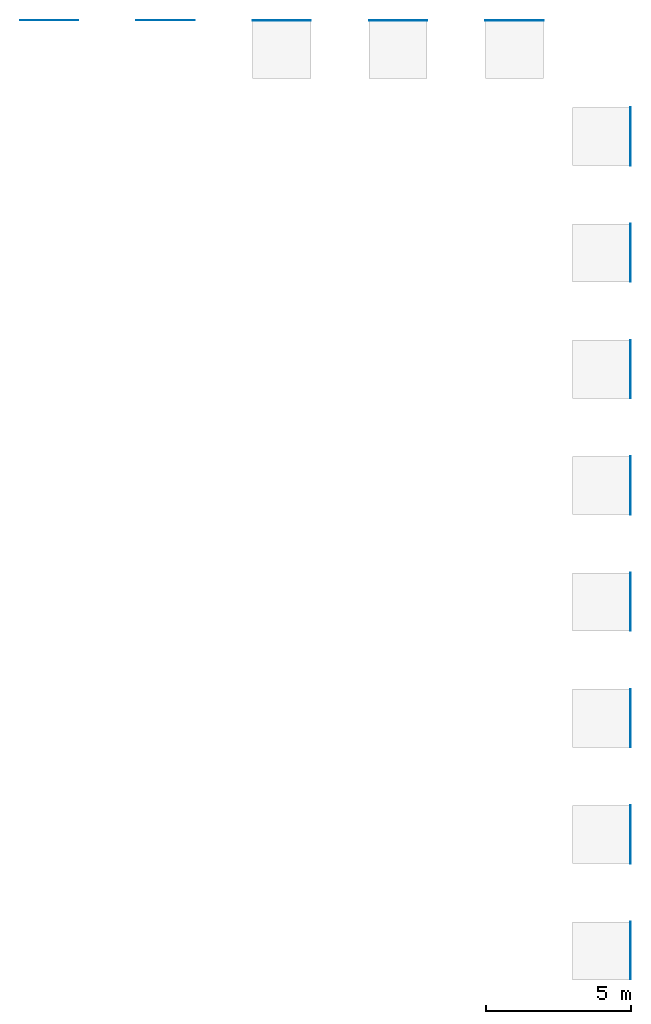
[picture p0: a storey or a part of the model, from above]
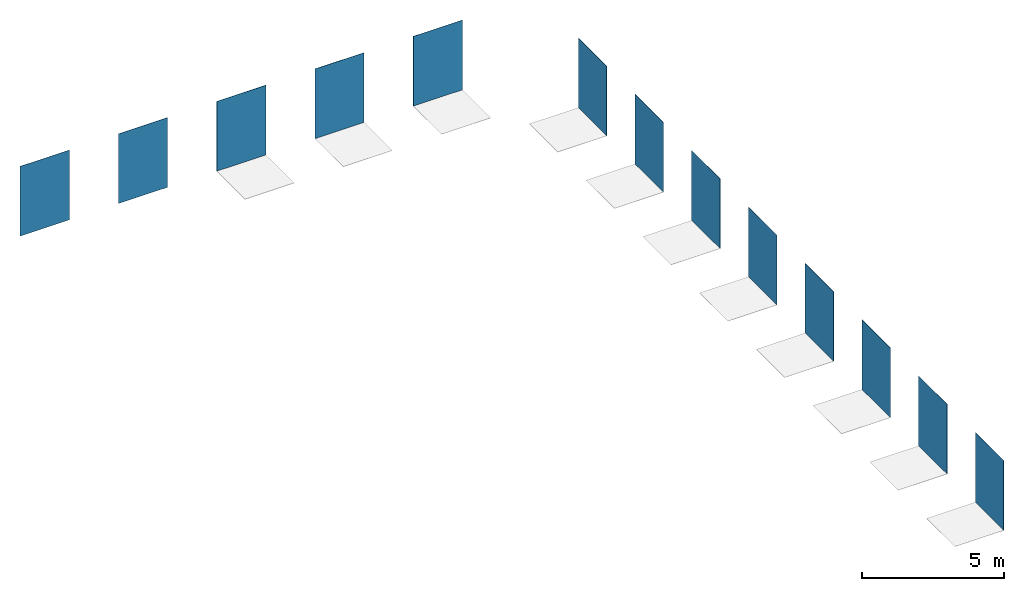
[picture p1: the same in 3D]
Properties of the parts of a building model (IFC2X3), part 2 of 2

# IfcWallStandardCase: Basic Wall:PGR_Porcelanosa_CeramicTiles_Boston_Grafito_Antislip-435x659mm-100180940, Basic Wall:PGR_Porcelanosa_CeramicTiles_Boston_Grafito_Antislip-435x659mm-100180940:212718
Type - NBS_Data - HasSurfaceRoughness: no; AbrasionResistance: 6: Intense-External Access; BreakingStrength: Average Value: 3310 N (Min. 1300 N); ChemicalResistance: Class 'A' for swimming pools and cleaning products (resists attack); minimum Class 'B' for acids and bases; Collection: STON-KER; CreationDate: 2018/07; Dcof: >0.42; FlexuralStrength: >40 N/mm²; FrostResistance: Conforms to ISO 10545-9; Group: BIa; MoistureExpansion: <0.1 mm/m; RampTest: R-12; RecycledContent: >6.5%; Series: Boston; SlipResistanceValuePendulumTestValue: CL3; StainResistance: Class 5: Easy cleaning with water; SurfaceQuality: Without surface defects; ThermalShockResistance: Conforms to ISO 10545–12; UpecC: n/a; UpecE: n/a; UpecP: n/a; UpecU: n/a; WaterAbsorption: E<=0.5%
COBie - AssetIdentifier: n/a; BarCode: n/a; InstallationDate: 1900-12-31T23:59:59; TagNumber: n/a; WarrantyStartDate: 1900-12-31T23:59:59

# IfcWallStandardCase: Basic Wall:PGR_Porcelanosa_CeramicTiles_Boston_Stone-435x659mm-100179183, Basic Wall:PGR_Porcelanosa_CeramicTiles_Boston_Stone-435x659mm-100179183:212739
In: Level 1
Type - PredefinedType: STANDARD; Material: PGR_Porcelanosa_CeramicTiles_Boston_Stone-435x659mm-100179183 10.5 mm
Type - NBS_General - Author: Porcelanosa Group; BIMObjectName: PGR_Porcelanosa_CeramicTiles_Boston_Stone-435x659mm-100179183; ManufacturerURL: www.porcelanosa.com; NBSDescription: Ceramic Tiles; NBSReference: 45-80-95/310; ProductInformation: http://calidad.info-grupo.com:8081/GeneraFicha3/PDF?articulo=100179183&lang=EN&un=0; Revision: n/a; Uniclass2015Code: Pr_35_93_96_19; Uniclass2015Title: Ceramic Tiles; Uniclass2015Version: Products v1.5; Version: 1
Type - COBie - AccessibilityPerformance: See ProductInformation (Technical PDF); AssetType: Fixed; Category: Walls; CodePerformance: ISO-13006:2012; UNE-EN 14411:2012; Color: Gris; Constituents: Clays, feldespat and glaze; Description: Rectified Porcelain tiles, BOSTON series from PORCELANOSA, GRIS color and MATTE finish, 43.5x65.9 cm (10.5 mm thickness), group BIa, according to UNE-EN 14411, water absortion capacity E<=0.5%, flexural strength >40 N/mm², breaking strength with an average value of 3310 N (Min. 1300 N) and slip resistance R-9; DurationUnit: year; ExpectedLife: 50; Features: See ProductInformation (Technical PDF); Grade: First quality; Manufacturer: bim.gp@porcelanosagrupo.com; ModelNumber: 100179183; ModelReference: Boston Stone 43.5x65.9 cm; Name: CeramicTiles_Boston_Stone-435x659mm-100179183; NominalHeight: 10.5 mm; NominalLength: 659 mm; NominalWidth: 435 mm; ReplacementCost: n/a; Shape: Rectangular; Size: 435x659x10.5 mm; Sustainability Performance: See ProductInformation (Technical PDF); WarrantyDescription: Manufacturer warranty, applicable worldwide, with the pertinent national legislation prevailing in all cases and covering at least a 3-year period; all products must have been manufactured and fitted in accordance with the Fabricator's Manual, and have been used and cared for in accordance with the Guide to Use, Cleaning and Care available on the web page www.porcelanosa.com; WarrantyDurationLabor: n/a; WarrantyDurationParts: 3; WarrantyDurationUnit: year; WarrantyGuarantorLabor: n/a; WarrantyGuarantorParts: bim.gp@porcelanosagrupo.com
Type - Pset_CoveringCommon - IsExternal: yes; Reference: n/a; AcousticRating: n/a; Finish: Tone Variations, Matte, Rectified, Stone; FireRating: A1; FlammabilityRating: Class 0; FragilityRating: n/a; Material: Ceramic; SurfaceSpreadOfFlame: Class 0; ThermalTransmittance: 219.048 kg/K/s3; TotalThickness: 10.5 mm
Type - IFC - IfcExportType: FLOORING; IfcExportAS: IfcCovering
Type - NBS_Data - HasSurfaceRoughness: no; AbrasionResistance: 6: Intense-External Access; BreakingStrength: Average Value: 3310 N (Min. 1300 N); ChemicalResistance: Class 'A' for swimming pools and cleaning products (resists attack); minimum Class 'B' for acids and bases; Collection: STON-KER; CreationDate: 2018/07; Dcof: >0.42; FlexuralStrength: >40 N/mm²; FrostResistance: Conforms to ISO 10545-9; Group: BIa; MoistureExpansion: <0.1 mm/m; RampTest: R-9; RecycledContent: >6.5%; Series: Boston; SlipResistanceValuePendulumTestValue: n/a; StainResistance: Class 5: Easy cleaning with water; SurfaceQuality: Without surface defects; ThermalShockResistance: Conforms to ISO 10545–12; UpecC: 2; UpecE: 3; UpecP: 3; UpecU: 2S; WaterAbsorption: E<=0.5%
COBie - AssetIdentifier: n/a; BarCode: n/a; InstallationDate: 1900-12-31T23:59:59; TagNumber: n/a; WarrantyStartDate: 1900-12-31T23:59:59

# IfcWallStandardCase: Basic Wall:PGR_Porcelanosa_CeramicTiles_Boston_Stone-596x1800mm-100179318, Basic Wall:PGR_Porcelanosa_CeramicTiles_Boston_Stone-596x1800mm-100179318:213871
In: Level 1
Type - PredefinedType: STANDARD; Material: PGR_Porcelanosa_CeramicTiles_Boston_Stone-596x1800mm-100179318 11.5 mm
Type - NBS_General - Author: Porcelanosa Group; BIMObjectName: PGR_Porcelanosa_CeramicTiles_Boston_Stone-596x1800mm-100179318; ManufacturerURL: www.porcelanosa.com; NBSDescription: Ceramic Tiles; NBSReference: 45-80-95/310; ProductInformation: http://calidad.info-grupo.com:8081/GeneraFicha3/PDF?articulo=100179318&lang=EN&un=0; Revision: n/a; Uniclass2015Code: Pr_35_93_96_19; Uniclass2015Title: Ceramic Tiles; Uniclass2015Version: Products v1.5; Version: 1
Type - COBie - AccessibilityPerformance: See ProductInformation (Technical PDF); AssetType: Fixed; Category: Walls; CodePerformance: ISO-13006:2012; UNE-EN 14411:2012; Color: Gris; Constituents: Clays, feldespat and glaze; Description: Rectified Porcelain tiles, BOSTON series from PORCELANOSA, GRIS color and MATTE finish, 59.6x180 cm (11.5 mm thickness), group BIa, according to UNE-EN 14411, water absortion capacity E<=0.5%, flexural strength >40 N/mm², breaking strength with an average value of 3310 N (Min. 1300 N) and slip resistance R-9; DurationUnit: year; ExpectedLife: 50; Features: See ProductInformation (Technical PDF); Grade: First quality; Manufacturer: bim.gp@porcelanosagrupo.com; ModelNumber: 100179318; ModelReference: Boston Stone 59.6x180 cm; Name: CeramicTiles_Boston_Stone-596x1800mm-100179318; NominalHeight: 11.5 mm; NominalLength: 1800 mm; NominalWidth: 596 mm; ReplacementCost: n/a; Shape: Rectangular; Size: 596x1800x11.5 mm; Sustainability Performance: See ProductInformation (Technical PDF); WarrantyDescription: Manufacturer warranty, applicable worldwide, with the pertinent national legislation prevailing in all cases and covering at least a 3-year period; all products must have been manufactured and fitted in accordance with the Fabricator's Manual, and have been used and cared for in accordance with the Guide to Use, Cleaning and Care available on the web page www.porcelanosa.com; WarrantyDurationLabor: n/a; WarrantyDurationParts: 3; WarrantyDurationUnit: year; WarrantyGuarantorLabor: n/a; WarrantyGuarantorParts: bim.gp@porcelanosagrupo.com
Type - Pset_CoveringCommon - IsExternal: yes; Reference: n/a; AcousticRating: n/a; Finish: Tone Variations, Matte, Rectified, Stone; FireRating: A1; FlammabilityRating: Class 0; FragilityRating: n/a; Material: Ceramic; SurfaceSpreadOfFlame: Class 0; ThermalTransmittance: 200 kg/K/s3; TotalThickness: 11.5 mm
Type - IFC - IfcExportType: FLOORING; IfcExportAS: IfcCovering
Type - NBS_Data - HasSurfaceRoughness: no; AbrasionResistance: 6: Intense-External Access; BreakingStrength: Average Value: 3310 N (Min. 1300 N); ChemicalResistance: Class 'A' for swimming pools and cleaning products (resists attack); minimum Class 'B' for acids and bases; Collection: STON-KER; CreationDate: 2018/07; Dcof: >0.42; FlexuralStrength: >40 N/mm²; FrostResistance: Conforms to ISO 10545-9; Group: BIa; MoistureExpansion: <0.1 mm/m; RampTest: R-9; RecycledContent: >6.5%; Series: Boston; SlipResistanceValuePendulumTestValue: CL1; StainResistance: Class 5: Easy cleaning with water; SurfaceQuality: Without surface defects; ThermalShockResistance: Conforms to ISO 10545–12; UpecC: n/a; UpecE: n/a; UpecP: n/a; UpecU: n/a; WaterAbsorption: E<=0.5%
COBie - AssetIdentifier: n/a; BarCode: n/a; InstallationDate: 1900-12-31T23:59:59; TagNumber: n/a; WarrantyStartDate: 1900-12-31T23:59:59

# IfcWallStandardCase: Basic Wall:PGR_Porcelanosa_CeramicTiles_Boston_Stone_Antislip-435x659mm-100180941, Basic Wall:PGR_Porcelanosa_CeramicTiles_Boston_Stone_Antislip-435x659mm-100180941:212760
In: Level 1
Type - PredefinedType: STANDARD; Material: PGR_Porcelanosa_CeramicTiles_Boston_Stone_Antislip-435x659mm-100180941 10.5 mm
Type - NBS_General - Author: Porcelanosa Group; BIMObjectName: PGR_Porcelanosa_CeramicTiles_Boston_Stone_Ant.-435x659mm-100180941; ManufacturerURL: www.porcelanosa.com; NBSDescription: Ceramic Tiles; NBSReference: 45-80-95/310; ProductInformation: http://calidad.info-grupo.com:8081/GeneraFicha3/PDF?articulo=100180941&lang=EN&un=0; Revision: n/a; Uniclass2015Code: Pr_35_93_96_19; Uniclass2015Title: Ceramic Tiles; Uniclass2015Version: Products v1.5; Version: 1
Type - COBie - AccessibilityPerformance: See ProductInformation (Technical PDF); AssetType: Fixed; Category: Walls; CodePerformance: ISO-13006:2012; UNE-EN 14411:2012; Color: Gris; Constituents: Clays, feldespat and glaze; Description: Rectified Porcelain tiles, BOSTON series from PORCELANOSA, GRIS color and MATTE finish, 43.5x65.9 cm (10.5 mm thickness), group BIa, according to UNE-EN 14411, water absortion capacity E<=0.5%, flexural strength >40 N/mm², breaking strength with an average value of 3310 N (Min. 1300 N) and slip resistance R-12; DurationUnit: year; ExpectedLife: 50; Features: See ProductInformation (Technical PDF); Grade: First quality; Manufacturer: bim.gp@porcelanosagrupo.com; ModelNumber: 100180941; ModelReference: Boston Stone Ant. 43.5x65.9 cm; Name: CeramicTiles_Boston_Stone_Ant.-435x659mm-100180941; NominalHeight: 10.5 mm; NominalLength: 659 mm; NominalWidth: 435 mm; ReplacementCost: n/a; Shape: Rectangular; Size: 435x659x10.5 mm; Sustainability Performance: See ProductInformation (Technical PDF); WarrantyDescription: Manufacturer warranty, applicable worldwide, with the pertinent national legislation prevailing in all cases and covering at least a 3-year period; all products must have been manufactured and fitted in accordance with the Fabricator's Manual, and have been used and cared for in accordance with the Guide to Use, Cleaning and Care available on the web page www.porcelanosa.com; WarrantyDurationLabor: n/a; WarrantyDurationParts: 3; WarrantyDurationUnit: year; WarrantyGuarantorLabor: n/a; WarrantyGuarantorParts: bim.gp@porcelanosagrupo.com
Type - Pset_CoveringCommon - IsExternal: yes; Reference: n/a; AcousticRating: n/a; Finish: Tone Variations, Matte, Non-Slip, Rectified, Stone; FireRating: A1; FlammabilityRating: Class 0; FragilityRating: n/a; Material: Ceramic; SurfaceSpreadOfFlame: Class 0; ThermalTransmittance: 219.048 kg/K/s3; TotalThickness: 10.5 mm
Type - IFC - IfcExportType: FLOORING; IfcExportAS: IfcCovering
Type - NBS_Data - HasSurfaceRoughness: no; AbrasionResistance: 6: Intense-External Access; BreakingStrength: Average Value: 3310 N (Min. 1300 N); ChemicalResistance: Class 'A' for swimming pools and cleaning products (resists attack); minimum Class 'B' for acids and bases; Collection: STON-KER; CreationDate: 2018/07; Dcof: >0.42; FlexuralStrength: >40 N/mm²; FrostResistance: Conforms to ISO 10545-9; Group: BIa; MoistureExpansion: <0.1 mm/m; RampTest: R-12; RecycledContent: >6.5%; Series: Boston; SlipResistanceValuePendulumTestValue: CL3; StainResistance: Class 5: Easy cleaning with water; SurfaceQuality: Without surface defects; ThermalShockResistance: Conforms to ISO 10545–12; UpecC: n/a; UpecE: n/a; UpecP: n/a; UpecU: n/a; WaterAbsorption: E<=0.5%
COBie - AssetIdentifier: n/a; BarCode: n/a; InstallationDate: 1900-12-31T23:59:59; TagNumber: n/a; WarrantyStartDate: 1900-12-31T23:59:59

# IfcWallStandardCase: Basic Wall:PGR_Porcelanosa_CeramicTiles_Boston_Topo-316x900mm-100179290, Basic Wall:PGR_Porcelanosa_CeramicTiles_Boston_Topo-316x900mm-100179290:219437
In: Level 1
Type - PredefinedType: STANDARD; Material: PGR_Porcelanosa_CeramicTiles_Boston_Topo-316x900mm-100179290 9 mm
Type - NBS_General - Author: Porcelanosa Group; BIMObjectName: PGR_Porcelanosa_CeramicTiles_Boston_Topo-316x900mm-100179290; ManufacturerURL: www.porcelanosa.com; NBSDescription: Ceramic Tiles; NBSReference: 45-80-95/310; ProductInformation: http://calidad.info-grupo.com:8081/GeneraFicha3/PDF?articulo=100179290&lang=EN&un=0; Revision: n/a; Uniclass2015Code: Pr_35_93_96_19; Uniclass2015Title: Ceramic Tiles; Uniclass2015Version: Products v1.5; Version: 1
Type - COBie - AccessibilityPerformance: See ProductInformation (Technical PDF); AssetType: Fixed; Category: Walls; CodePerformance: ISO-13006:2012; UNE-EN 14411:2012; Color: Marron; Constituents: Clays, feldespat and glaze; Description: Rectified Monoporous, BOSTON series from PORCELANOSA, MARRON color and MATTE finish, 31.6x90 cm (9 mm thickness), group BIII, according to UNE-EN 14411, water absortion capacity 10%<=E<=20%, flexural strength >23 N/mm² and breaking strength with an average value of 1337 N (Min. 600 N); DurationUnit: year; ExpectedLife: 50; Features: See ProductInformation (Technical PDF); Grade: First quality; Manufacturer: bim.gp@porcelanosagrupo.com; ModelNumber: 100179290; ModelReference: Boston Topo 31.6x90 cm; Name: CeramicTiles_Boston_Topo-316x900mm-100179290; NominalHeight: 9 mm; NominalLength: 900 mm; NominalWidth: 316 mm; ReplacementCost: n/a; Shape: Rectangular; Size: 316x900x9 mm; Sustainability Performance: See ProductInformation (Technical PDF); WarrantyDescription: Manufacturer warranty, applicable worldwide, with the pertinent national legislation prevailing in all cases and covering at least a 3-year period; all products must have been manufactured and fitted in accordance with the Fabricator's Manual, and have been used and cared for in accordance with the Guide to Use, Cleaning and Care available on the web page www.porcelanosa.com; WarrantyDurationLabor: n/a; WarrantyDurationParts: 3; WarrantyDurationUnit: year; WarrantyGuarantorLabor: n/a; WarrantyGuarantorParts: bim.gp@porcelanosagrupo.com
Type - Pset_CoveringCommon - Reference: n/a; AcousticRating: n/a; Finish: Tone Variations, Matte, Rectified, Stone; FireRating: A1; FlammabilityRating: Class 0; FragilityRating: n/a; IsExternal: no; Material: Ceramic; SurfaceSpreadOfFlame: Class 0; ThermalTransmittance: 255.556 kg/K/s3; TotalThickness: 9 mm
Type - IFC - IfcExportType: CLADDING; IfcExportAS: IfcCovering
Type - NBS_Data - HasSurfaceRoughness: no; AbrasionResistance: 1: Wall Tiles; BreakingStrength: Average Value: 1337 N (Min. 600 N); ChemicalResistance: Class 'A' for swimming pools and cleaning products (resists attack); minimum Class 'B' for acids and bases; Collection: Revestimiento Ceramico Rectificado; CreationDate: 2018/07; Dcof: n/a; FlexuralStrength: >23 N/mm²; FrostResistance: n/a; Group: BIII; MoistureExpansion: <0.1 mm/m; RampTest: n/a; RecycledContent: >18%; Series: Boston; SlipResistanceValuePendulumTestValue: n/a; StainResistance: Class 5: Easy cleaning with water; SurfaceQuality: Without surface defects; ThermalShockResistance: Conforms to ISO 10545–12; UpecC: n/a; UpecE: n/a; UpecP: n/a; UpecU: n/a; WaterAbsorption: 10%<=E<=20%
COBie - AssetIdentifier: n/a; BarCode: n/a; InstallationDate: 1900-12-31T23:59:59; TagNumber: n/a; WarrantyStartDate: 1900-12-31T23:59:59

# IfcWallStandardCase: Basic Wall:PGR_Porcelanosa_CeramicTiles_Boston_Topo-435x659mm-100179203, Basic Wall:PGR_Porcelanosa_CeramicTiles_Boston_Topo-435x659mm-100179203:212781
In: Level 1
Type - PredefinedType: STANDARD; Material: PGR_Porcelanosa_CeramicTiles_Boston_Topo-435x659mm-100179203 10.5 mm
Type - NBS_General - Author: Porcelanosa Group; BIMObjectName: PGR_Porcelanosa_CeramicTiles_Boston_Topo-435x659mm-100179203; ManufacturerURL: www.porcelanosa.com; NBSDescription: Ceramic Tiles; NBSReference: 45-80-95/310; ProductInformation: http://calidad.info-grupo.com:8081/GeneraFicha3/PDF?articulo=100179203&lang=EN&un=0; Revision: n/a; Uniclass2015Code: Pr_35_93_96_19; Uniclass2015Title: Ceramic Tiles; Uniclass2015Version: Products v1.5; Version: 1
Type - COBie - AccessibilityPerformance: See ProductInformation (Technical PDF); AssetType: Fixed; Category: Pr_35_93_96_19:Ceramic Tiles; CodePerformance: ISO-13006:2012; UNE-EN 14411:2012; Color: Marron; Constituents: Clays, feldespat and glaze; Description: Rectified Porcelain tiles, BOSTON series from PORCELANOSA, MARRON color and MATTE finish, 43.5x65.9 cm (10.5 mm thickness), group BIa, according to UNE-EN 14411, water absortion capacity E<=0.5%, flexural strength >40 N/mm², breaking strength with an average value of 3310 N (Min. 1300 N) and slip resistance R-9; DurationUnit: year; ExpectedLife: 50; Features: See ProductInformation (Technical PDF); Grade: First quality; Manufacturer: bim.gp@porcelanosagrupo.com; ModelNumber: 100179203; ModelReference: Boston Topo 43.5x65.9 cm; Name: CeramicTiles_Boston_Topo-435x659mm-100179203; NominalHeight: 10.5 mm; NominalLength: 659 mm; NominalWidth: 435 mm; ReplacementCost: n/a; Shape: Rectangular; Size: 435x659x10.5 mm; Sustainability Performance: See ProductInformation (Technical PDF); WarrantyDescription: Manufacturer warranty, applicable worldwide, with the pertinent national legislation prevailing in all cases and covering at least a 3-year period; all products must have been manufactured and fitted in accordance with the Fabricator's Manual, and have been used and cared for in accordance with the Guide to Use, Cleaning and Care available on the web page www.porcelanosa.com; WarrantyDurationLabor: n/a; WarrantyDurationParts: 3; WarrantyDurationUnit: year; WarrantyGuarantorLabor: n/a; WarrantyGuarantorParts: bim.gp@porcelanosagrupo.com
Type - Pset_CoveringCommon - IsExternal: yes; Reference: n/a; AcousticRating: n/a; Finish: Tone Variations, Matte, Rectified, Stone; FireRating: A1; FlammabilityRating: Class 0; FragilityRating: n/a; Material: Ceramic; SurfaceSpreadOfFlame: Class 0; ThermalTransmittance: 219.048 kg/K/s3; TotalThickness: 10.5 mm
Type - IFC - IfcExportType: FLOORING; IfcExportAS: IfcCovering
Type - NBS_Data - HasSurfaceRoughness: no; AbrasionResistance: 6: Intense-External Access; BreakingStrength: Average Value: 3310 N (Min. 1300 N); ChemicalResistance: Class 'A' for swimming pools and cleaning products (resists attack); minimum Class 'B' for acids and bases; Collection: STON-KER; CreationDate: 2018/07; Dcof: >0.42; FlexuralStrength: >40 N/mm²; FrostResistance: Conforms to ISO 10545-9; Group: BIa; MoistureExpansion: <0.1 mm/m; RampTest: R-9; RecycledContent: >6.5%; Series: Boston; SlipResistanceValuePendulumTestValue: CL1; StainResistance: Class 5: Easy cleaning with water; SurfaceQuality: Without surface defects; ThermalShockResistance: Conforms to ISO 10545–12; UpecC: 2; UpecE: 3; UpecP: 3; UpecU: 2S; WaterAbsorption: E<=0.5%
COBie - AssetIdentifier: n/a; BarCode: n/a; InstallationDate: 1900-12-31T23:59:59; TagNumber: n/a; WarrantyStartDate: 1900-12-31T23:59:59

# IfcWallStandardCase: Basic Wall:PGR_Porcelanosa_CeramicTiles_Boston_Topo-596x1800mm-100179326, Basic Wall:PGR_Porcelanosa_CeramicTiles_Boston_Topo-596x1800mm-100179326:213892
In: Level 1
Type - PredefinedType: STANDARD; Material: PGR_Porcelanosa_CeramicTiles_Boston_Topo-596x1800mm-100179326 11.5 mm
Type - NBS_General - Author: Porcelanosa Group; BIMObjectName: PGR_Porcelanosa_CeramicTiles_Boston_Topo-596x1800mm-100179326; ManufacturerURL: www.porcelanosa.com; NBSDescription: Ceramic Tiles; NBSReference: 45-80-95/310; ProductInformation: http://calidad.info-grupo.com:8081/GeneraFicha3/PDF?articulo=100179326&lang=EN&un=0; Revision: n/a; Uniclass2015Code: Pr_35_93_96_19; Uniclass2015Title: Ceramic Tiles; Uniclass2015Version: Products v1.5; Version: 1
Type - COBie - AccessibilityPerformance: See ProductInformation (Technical PDF); AssetType: Fixed; Category: Walls; CodePerformance: ISO-13006:2012; UNE-EN 14411:2012; Color: Marron; Constituents: Clays, feldespat and glaze; Description: Rectified Porcelain tiles, BOSTON series from PORCELANOSA, MARRON color and MATTE finish, 59.6x180 cm (11.5 mm thickness), group BIa, according to UNE-EN 14411, water absortion capacity E<=0.5%, flexural strength >40 N/mm², breaking strength with an average value of 3310 N (Min. 1300 N) and slip resistance R-9; DurationUnit: year; ExpectedLife: 50; Features: See ProductInformation (Technical PDF); Grade: First quality; Manufacturer: bim.gp@porcelanosagrupo.com; ModelNumber: 100179326; ModelReference: Boston Topo 59.6x180 cm; Name: CeramicTiles_Boston_Topo-596x1800mm-100179326; NominalHeight: 11.5 mm; NominalLength: 1800 mm; NominalWidth: 596 mm; ReplacementCost: n/a; Shape: Rectangular; Size: 596x1800x11.5 mm; Sustainability Performance: See ProductInformation (Technical PDF); WarrantyDescription: Manufacturer warranty, applicable worldwide, with the pertinent national legislation prevailing in all cases and covering at least a 3-year period; all products must have been manufactured and fitted in accordance with the Fabricator's Manual, and have been used and cared for in accordance with the Guide to Use, Cleaning and Care available on the web page www.porcelanosa.com; WarrantyDurationLabor: n/a; WarrantyDurationParts: 3; WarrantyDurationUnit: year; WarrantyGuarantorLabor: n/a; WarrantyGuarantorParts: bim.gp@porcelanosagrupo.com
Type - Pset_CoveringCommon - IsExternal: yes; Reference: n/a; AcousticRating: n/a; Finish: Tone Variations, Matte, Rectified, Stone; FireRating: A1; FlammabilityRating: Class 0; FragilityRating: n/a; Material: Ceramic; SurfaceSpreadOfFlame: Class 0; ThermalTransmittance: 200 kg/K/s3; TotalThickness: 11.5 mm
Type - IFC - IfcExportType: FLOORING; IfcExportAS: IfcCovering
Type - NBS_Data - HasSurfaceRoughness: no; AbrasionResistance: 6: Intense-External Access; BreakingStrength: Average Value: 3310 N (Min. 1300 N); ChemicalResistance: Class 'A' for swimming pools and cleaning products (resists attack); minimum Class 'B' for acids and bases; Collection: STON-KER; CreationDate: 2018/07; Dcof: >0.42; FlexuralStrength: >40 N/mm²; FrostResistance: Conforms to ISO 10545-9; Group: BIa; MoistureExpansion: <0.1 mm/m; RampTest: R-9; RecycledContent: >6.5%; Series: Boston; SlipResistanceValuePendulumTestValue: CL1; StainResistance: Class 5: Easy cleaning with water; SurfaceQuality: Without surface defects; ThermalShockResistance: Conforms to ISO 10545–12; UpecC: n/a; UpecE: n/a; UpecP: n/a; UpecU: n/a; WaterAbsorption: E<=0.5%
COBie - AssetIdentifier: n/a; BarCode: n/a; InstallationDate: 1900-12-31T23:59:59; TagNumber: n/a; WarrantyStartDate: 1900-12-31T23:59:59

# IfcWallStandardCase: Basic Wall:PGR_Porcelanosa_CeramicTiles_Boston_Topo-596x596mm-100179350, Basic Wall:PGR_Porcelanosa_CeramicTiles_Boston_Topo-596x596mm-100179350:210442
In: Level 1
Type - PredefinedType: STANDARD; Material: PGR_Porcelanosa_CeramicTiles_Boston_Topo-596x596mm-100179350 10.5 mm
Type - NBS_General - Author: Porcelanosa Group; BIMObjectName: PGR_Porcelanosa_CeramicTiles_Boston_Topo-596x596mm-100179350; ManufacturerURL: www.porcelanosa.com; NBSDescription: Ceramic Tiles; NBSReference: 45-80-95/310; ProductInformation: http://calidad.info-grupo.com:8081/GeneraFicha3/PDF?articulo=100179350&lang=EN&un=0; Revision: n/a; Uniclass2015Code: Pr_35_93_96_19; Uniclass2015Title: Ceramic Tiles; Uniclass2015Version: Products v1.5; Version: 1
Type - COBie - AccessibilityPerformance: See ProductInformation (Technical PDF); AssetType: Fixed; Category: Pr_35_93_96_19:Ceramic Tiles; CodePerformance: ISO-13006:2012; UNE-EN 14411:2012; Color: Marron; Constituents: Clays, feldespat and glaze; Description: Rectified Porcelain tiles, BOSTON series from PORCELANOSA, MARRON color and MATTE finish, 59.6x59.6 cm (10.3 mm thickness), group BIa, according to UNE-EN 14411, water absortion capacity E<=0.5%, flexural strength >40 N/mm², breaking strength with an average value of 3310 N (Min. 1300 N) and slip resistance R-9; DurationUnit: year; ExpectedLife: 50; Features: See ProductInformation (Technical PDF); Grade: First quality; Manufacturer: bim.gp@porcelanosagrupo.com; ModelNumber: 100179350; ModelReference: Boston Topo 59.6x59.6 cm; Name: CeramicTiles_Boston_Topo-596x596mm-100179350; NominalHeight: 10.3 mm; NominalLength: 596 mm; NominalWidth: 596 mm; ReplacementCost: n/a; Shape: Squared; Size: 596x596x10.3 mm; Sustainability Performance: See ProductInformation (Technical PDF); WarrantyDescription: Manufacturer warranty, applicable worldwide, with the pertinent national legislation prevailing in all cases and covering at least a 3-year period; all products must have been manufactured and fitted in accordance with the Fabricator's Manual, and have been used and cared for in accordance with the Guide to Use, Cleaning and Care available on the web page www.porcelanosa.com; WarrantyDurationLabor: n/a; WarrantyDurationParts: 3; WarrantyDurationUnit: year; WarrantyGuarantorLabor: n/a; WarrantyGuarantorParts: bim.gp@porcelanosagrupo.com
Type - Pset_CoveringCommon - IsExternal: yes; Reference: n/a; AcousticRating: n/a; Finish: Tone Variations, Matte, Rectified, Stone; FireRating: A1; FlammabilityRating: Class 0; FragilityRating: n/a; Material: Ceramic; SurfaceSpreadOfFlame: Class 0; ThermalTransmittance: 223.301 kg/K/s3; TotalThickness: 10.3 mm
Type - IFC - IfcExportType: FLOORING; IfcExportAS: IfcCovering
Type - NBS_Data - HasSurfaceRoughness: no; AbrasionResistance: 6: Intense-External Access; BreakingStrength: Average Value: 3310 N (Min. 1300 N); ChemicalResistance: Class 'A' for swimming pools and cleaning products (resists attack); minimum Class 'B' for acids and bases; Collection: STON-KER; CreationDate: 2018/07; Dcof: >0.42; FlexuralStrength: >40 N/mm²; FrostResistance: Conforms to ISO 10545-9; Group: BIa; MoistureExpansion: <0.1 mm/m; RampTest: R-9; RecycledContent: >6.5%; Series: Boston; SlipResistanceValuePendulumTestValue: CL1; StainResistance: Class 5: Easy cleaning with water; SurfaceQuality: Without surface defects; ThermalShockResistance: Conforms to ISO 10545–12; UpecC: 2; UpecE: 3; UpecP: 3; UpecU: 2S; WaterAbsorption: E<=0.5%
COBie - AssetIdentifier: n/a; BarCode: n/a; InstallationDate: 1900-12-31T23:59:59; TagNumber: n/a; WarrantyStartDate: 1900-12-31T23:59:59

# IfcWallStandardCase: Basic Wall:PGR_Porcelanosa_CeramicTiles_Boston_Topo_Antislip-435x659mm-100180913, Basic Wall:PGR_Porcelanosa_CeramicTiles_Boston_Topo_Antislip-435x659mm-100180913:213482
In: Level 1
Type - PredefinedType: STANDARD; Material: PGR_Porcelanosa_CeramicTiles_Boston_Topo_Antislip-435x659mm-100180913 10.5 mm
Type - NBS_General - Author: Porcelanosa Group; BIMObjectName: PGR_Porcelanosa_CeramicTiles_Boston_Topo_Ant.-435x659mm-100180913; ManufacturerURL: www.porcelanosa.com; NBSDescription: Ceramic Tiles; NBSReference: 45-80-95/310; ProductInformation: http://calidad.info-grupo.com:8081/GeneraFicha3/PDF?articulo=100180913&lang=EN&un=0; Revision: n/a; Uniclass2015Code: Pr_35_93_96_19; Uniclass2015Title: Ceramic Tiles; Uniclass2015Version: Products v1.5; Version: 1
Type - COBie - AccessibilityPerformance: See ProductInformation (Technical PDF); AssetType: Fixed; Category: Pr_35_93_96_19:Ceramic Tiles; CodePerformance: ISO-13006:2012; UNE-EN 14411:2012; Color: Marron; Constituents: Clays, feldespat and glaze; Description: Rectified Porcelain tiles, BOSTON series from PORCELANOSA, MARRON color and MATTE finish, 43.5x65.9 cm (10.5 mm thickness), group BIa, according to UNE-EN 14411, water absortion capacity E<=0.5%, flexural strength >40 N/mm², breaking strength with an average value of 3310 N (Min. 1300 N) and slip resistance R-12; DurationUnit: year; ExpectedLife: 50; Features: See ProductInformation (Technical PDF); Grade: First quality; Manufacturer: bim.gp@porcelanosagrupo.com; ModelNumber: 100180913; ModelReference: Boston Topo Ant. 43.5x65.9 cm; Name: CeramicTiles_Boston_Topo_Ant.-435x659mm-100180913; NominalHeight: 10.5 mm; NominalLength: 659 mm; NominalWidth: 435 mm; ReplacementCost: n/a; Shape: Rectangular; Size: 435x659x10.5 mm; Sustainability Performance: See ProductInformation (Technical PDF); WarrantyDescription: Manufacturer warranty, applicable worldwide, with the pertinent national legislation prevailing in all cases and covering at least a 3-year period; all products must have been manufactured and fitted in accordance with the Fabricator's Manual, and have been used and cared for in accordance with the Guide to Use, Cleaning and Care available on the web page www.porcelanosa.com; WarrantyDurationLabor: n/a; WarrantyDurationParts: 3; WarrantyDurationUnit: year; WarrantyGuarantorLabor: n/a; WarrantyGuarantorParts: bim.gp@porcelanosagrupo.com
Type - Pset_CoveringCommon - IsExternal: yes; Reference: n/a; AcousticRating: n/a; Finish: Tone Variations, Matte, Non-Slip, Rectified, Stone; FireRating: A1; FlammabilityRating: Class 0; FragilityRating: n/a; Material: Ceramic; SurfaceSpreadOfFlame: Class 0; ThermalTransmittance: 219.048 kg/K/s3; TotalThickness: 10.5 mm
Type - IFC - IfcExportType: FLOORING; IfcExportAS: IfcCovering
Type - NBS_Data - HasSurfaceRoughness: no; AbrasionResistance: 6: Intense-External Access; BreakingStrength: Average Value: 3310 N (Min. 1300 N); ChemicalResistance: Class 'A' for swimming pools and cleaning products (resists attack); minimum Class 'B' for acids and bases; Collection: STON-KER; CreationDate: 2018/07; Dcof: >0.42; FlexuralStrength: >40 N/mm²; FrostResistance: Conforms to ISO 10545-9; Group: BIa; MoistureExpansion: <0.1 mm/m; RampTest: R-12; RecycledContent: >6.5%; Series: Boston; SlipResistanceValuePendulumTestValue: CL3; StainResistance: Class 5: Easy cleaning with water; SurfaceQuality: Without surface defects; ThermalShockResistance: Conforms to ISO 10545–12; UpecC: n/a; UpecE: n/a; UpecP: n/a; UpecU: n/a; WaterAbsorption: E<=0.5%
COBie - AssetIdentifier: n/a; BarCode: n/a; InstallationDate: 1900-12-31T23:59:59; TagNumber: n/a; WarrantyStartDate: 1900-12-31T23:59:59
